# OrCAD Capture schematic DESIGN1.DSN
size A

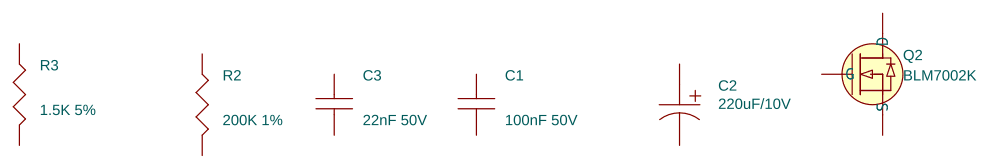
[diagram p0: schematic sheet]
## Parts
C1  100nF 50V  [0805]
C2  220uF/10V  [ECS8D3X8D3]
C3  22nF 50V  [CAPC1608]
Q2  BLM7002K  [SOT23]
R2  200K 1%  [1-8W]
R3  1.5K 5%  [RESC1005]

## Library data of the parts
C1 = CC0805_104_Y5V_50V: 电容 C-CERAMIC, CHIP ; 100nF, +80-20%, 50V, Y5V, TP, 2012 Pb Free; Kinds: 优选; MaterialType: SMT; Part Number: 1.GYR.2203.000192; PartName: 电容; Part_Type: library
C2 = ECS220uF_10V_8.3_8.3: 普通电解电容: CD-220uF 10V, 20% 105C（SMD8.3*8.3）; Kinds: 优选; MaterialType: SMT; PartName: 电解电容; Part_Type: library
C3 = CC0603_223_Y5V_50V: C-CERAMIC,CHIP;22nF,+80-20%,50V,Y5V,TP,1608; Kinds: 次选; MaterialType: SMT; PartName: 片状电容; Part_Type: library
Q2 = NMOS_BLM7002K: N-MOS:BLM7002K,丝印7002K,BELLING,VDS60,VGS20,ID0.3A,PD0.35W,RDS(ON)3 ohm,SOT-23,; Kinds: 优选; MaterialType: SMT; PartName: 三极管; Part_Type: library
R2 = RMF_200K_1%_1_8W: 电阻 R-MF 200K ohm 1% 1/8WW DISTANCE 7.5mm Pb free; Kinds: 优选; MaterialType: DIP; PartName: 电阻; Part_Type: library
R3 = RC0402_152_5%: R-CHIP; 1.5K ohm, 5%, 1/16W, DA, TP, 1005; Kinds: 优选; MaterialType: SMT; PartName: 片状电阻; Part_Type: library

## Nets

Not connected (* = marked no-connect by the designer): C1 1 2; C2 1 2; C3 1 2; Q2 1(G) 2(S) 3(D); R2 1 2; R3 1 2
